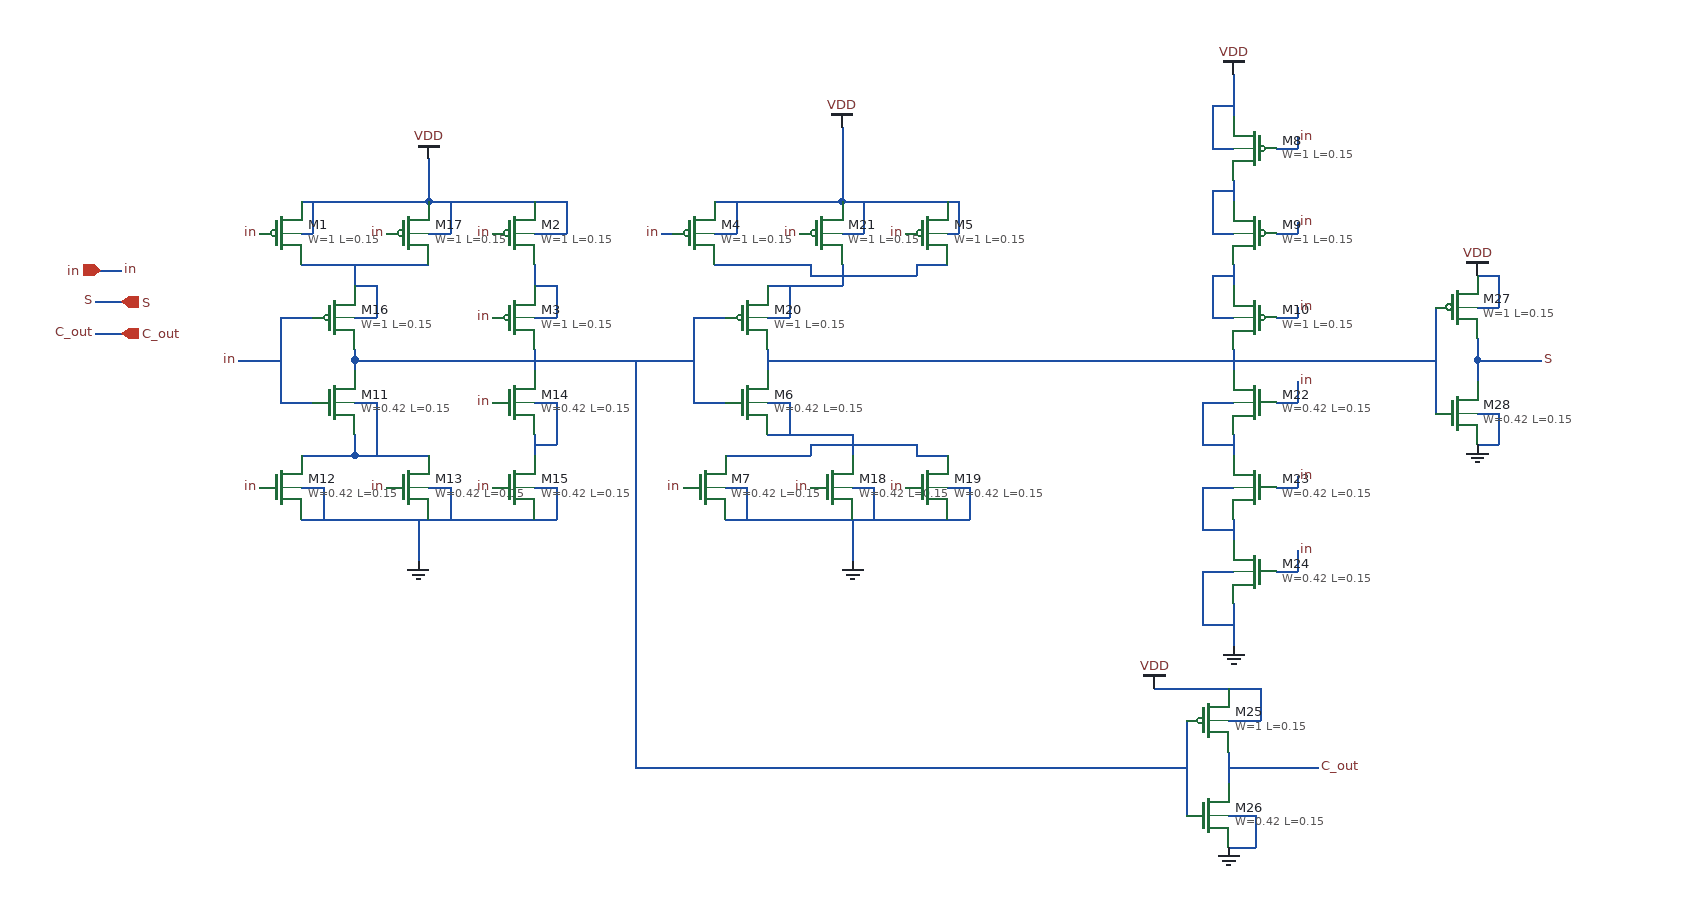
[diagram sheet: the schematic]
v {xschem version=3.4.3 file_version=1.2
}
G {}
K {}
V {}
S {}
E {}
N 60 20 180 20 {
lab=VDD}
N 180 20 280 20 {
lab=VDD}
N 180 -20 180 20 {
lab=VDD}
N 570 -50 570 20 {
lab=VDD}
N 450 20 570 20 {
lab=VDD}
N 570 20 670 20 {
lab=VDD}
N 60 80 180 80 {
lab=#net1}
N 280 80 280 100 {
lab=#net2}
N 280 160 280 180 {
lab=#net3}
N 110 170 280 170 {
lab=#net3}
N 110 160 110 170 {
lab=#net3}
N 110 170 110 180 {
lab=#net3}
N 110 80 110 100 {
lab=#net1}
N 110 240 110 260 {
lab=#net4}
N 110 260 180 260 {
lab=#net4}
N 60 260 110 260 {
lab=#net4}
N 170 320 170 360 {
lab=GND}
N 460 320 670 320 {
lab=GND}
N 580 320 580 360 {
lab=GND}
N 450 80 540 80 {
lab=#net5}
N 540 80 540 90 {
lab=#net5}
N 540 90 640 90 {
lab=#net5}
N 640 80 640 90 {
lab=#net5}
N 640 80 670 80 {
lab=#net5}
N 570 80 570 100 {
lab=#net6}
N 500 100 570 100 {
lab=#net6}
N 60 320 180 320 {
lab=GND}
N 180 320 280 320 {
lab=GND}
N 500 160 500 180 {
lab=#net7}
N 460 260 540 260 {
lab=#net8}
N 540 250 540 260 {
lab=#net8}
N 540 250 640 250 {
lab=#net8}
N 640 250 640 260 {
lab=#net8}
N 640 260 670 260 {
lab=#net8}
N 580 240 580 260 {
lab=#net9}
N 500 240 570 240 {
lab=#net9}
N 570 240 580 240 {
lab=#net9}
N 430 130 460 130 {
lab=#net3}
N 430 130 430 210 {
lab=#net3}
N 430 210 460 210 {
lab=#net3}
N 280 170 430 170 {
lab=#net3}
N 40 130 70 130 {
lab=in}
N 40 130 40 210 {
lab=in}
N 40 210 70 210 {
lab=in}
N 500 170 1070 170 {
lab=#net7}
N 940 160 940 170 {
lab=#net7}
N 940 170 940 180 {
lab=#net7}
N 940 80 940 100 {
lab=#net10}
N 940 0 940 20 {
lab=#net11}
N 940 240 940 260 {
lab=#net12}
N 940 320 940 340 {
lab=#net13}
N 940 -100 940 -60 {
lab=VDD}
N 940 400 940 440 {
lab=GND}
N -130 85 -110 85 {
lab=in}
N -135 115 -110 115 {
lab=S}
N 0 170 40 170 {
lab=in}
N 280 240 280 260 {
lab=#net14}
N 980 -30 1000 -30 {
lab=in}
N 1000 -40 1000 -30 {
lab=in}
N 1000 40 1000 50 {
lab=in}
N 980 50 1000 50 {
lab=in}
N 1000 120 1000 130 {
lab=in}
N 980 130 1000 130 {
lab=in}
N 1000 190 1000 210 {
lab=in}
N 980 210 990 210 {
lab=in}
N 990 210 1000 210 {
lab=in}
N 1000 280 1000 290 {
lab=in}
N 980 290 990 290 {
lab=in}
N 990 290 1000 290 {
lab=in}
N 1000 360 1000 370 {
lab=B}
N 980 370 1000 370 {
lab=B}
N 1000 350 1000 360 {
lab=B}
N 70 20 70 50 {
lab=VDD}
N 60 50 70 50 {
lab=VDD}
N 200 20 200 50 {
lab=VDD}
N 180 50 200 50 {
lab=VDD}
N 280 20 310 20 {
lab=VDD}
N 310 20 310 50 {
lab=VDD}
N 280 50 310 50 {
lab=VDD}
N 110 100 130 100 {
lab=#net1}
N 130 100 130 130 {
lab=#net1}
N 110 130 120 130 {
lab=#net1}
N 120 130 130 130 {
lab=#net1}
N 280 100 300 100 {
lab=#net2}
N 300 100 300 130 {
lab=#net2}
N 280 130 300 130 {
lab=#net2}
N 470 20 470 50 {
lab=VDD}
N 450 50 470 50 {
lab=VDD}
N 110 210 130 210 {
lab=#net4}
N 130 210 130 260 {
lab=#net4}
N 60 290 80 290 {
lab=GND}
N 80 290 80 320 {
lab=GND}
N 180 290 200 290 {
lab=GND}
N 200 290 200 320 {
lab=GND}
N 280 290 300 290 {
lab=GND}
N 300 290 300 320 {
lab=GND}
N 280 320 300 320 {
lab=GND}
N 460 290 480 290 {
lab=GND}
N 480 290 480 320 {
lab=GND}
N 500 210 520 210 {
lab=#net9}
N 520 210 520 240 {
lab=#net9}
N 500 130 520 130 {
lab=#net6}
N 520 100 520 130 {
lab=#net6}
N 580 290 600 290 {
lab=GND}
N 600 290 600 320 {
lab=GND}
N 670 290 690 290 {
lab=GND}
N 690 290 690 320 {
lab=GND}
N 670 320 690 320 {
lab=GND}
N 570 50 590 50 {
lab=VDD}
N 590 20 590 50 {
lab=VDD}
N 670 50 680 50 {
lab=VDD}
N 680 20 680 50 {
lab=VDD}
N 670 20 680 20 {
lab=VDD}
N 920 50 940 50 {
lab=#net11}
N 920 10 920 50 {
lab=#net11}
N 920 10 940 10 {
lab=#net11}
N 920 130 940 130 {
lab=#net10}
N 920 90 920 130 {
lab=#net10}
N 920 90 940 90 {
lab=#net10}
N 910 210 940 210 {
lab=#net12}
N 910 210 910 250 {
lab=#net12}
N 910 250 940 250 {
lab=#net12}
N 910 290 940 290 {
lab=#net13}
N 910 290 910 330 {
lab=#net13}
N 910 330 940 330 {
lab=#net13}
N 910 370 940 370 {
lab=GND}
N 910 370 910 420 {
lab=GND}
N 910 420 940 420 {
lab=GND}
N 280 210 300 210 {
lab=#net14}
N 300 210 300 250 {
lab=#net14}
N 280 250 300 250 {
lab=#net14}
N 920 -30 940 -30 {
lab=VDD}
N 920 -70 920 -30 {
lab=VDD}
N 920 -70 940 -70 {
lab=VDD}
N 1070 170 1130 170 {
lab=#net7}
N 1130 140 1130 220 {
lab=#net7}
N 1170 170 1170 190 {
lab=S}
N 1130 130 1130 140 {
lab=#net7}
N 1170 160 1170 170 {
lab=S}
N 1170 170 1230 170 {
lab=S}
N 1170 150 1170 160 {
lab=S}
N 1130 120 1130 130 {
lab=#net7}
N 1170 120 1190 120 {
lab=VDD}
N 1190 90 1190 120 {
lab=VDD}
N 1170 90 1190 90 {
lab=VDD}
N 1170 220 1190 220 {
lab=GND}
N 1170 250 1190 250 {
lab=GND}
N 1190 220 1190 250 {
lab=GND}
N 375 170 375 555 {
lab=#net3}
N 375 555 870 555 {
lab=#net3}
N 870 555 895 555 {
lab=#net3}
N 935 550 935 570 {
lab=C_out}
N 935 540 935 550 {
lab=C_out}
N 935 555 1020 555 {
lab=C_out}
N 865 480 935 480 {
lab=VDD}
N 935 510 965 510 {
lab=VDD}
N 965 480 965 510 {
lab=VDD}
N 935 480 965 480 {
lab=VDD}
N 935 600 960 600 {
lab=GND}
N 960 600 960 630 {
lab=GND}
N 945 630 960 630 {
lab=GND}
N 935 630 945 630 {
lab=GND}
N -135 145 -110 145 {
lab=C_out}
N 895 510 895 600 {
lab=#net3}
N 400 50 410 50 {
lab=in}
C {sky130_fd_pr/pfet_01v8.sym} 40 50 0 0 {name=M1
L=0.15
W=1
nf=1
mult=1
ad="'int((nf+1)/2) * W/nf * 0.29'" 
pd="'2*int((nf+1)/2) * (W/nf + 0.29)'"
as="'int((nf+2)/2) * W/nf * 0.29'" 
ps="'2*int((nf+2)/2) * (W/nf + 0.29)'"
nrd="'0.29 / W'" nrs="'0.29 / W'"
sa=0 sb=0 sd=0
model=pfet_01v8
spiceprefix=X
}
C {sky130_fd_pr/pfet_01v8.sym} 260 50 0 0 {name=M2
L=0.15
W=1
nf=1
mult=1
ad="'int((nf+1)/2) * W/nf * 0.29'" 
pd="'2*int((nf+1)/2) * (W/nf + 0.29)'"
as="'int((nf+2)/2) * W/nf * 0.29'" 
ps="'2*int((nf+2)/2) * (W/nf + 0.29)'"
nrd="'0.29 / W'" nrs="'0.29 / W'"
sa=0 sb=0 sd=0
model=pfet_01v8
spiceprefix=X
}
C {sky130_fd_pr/pfet_01v8.sym} 260 130 0 0 {name=M3
L=0.15
W=1
nf=1
mult=1
ad="'int((nf+1)/2) * W/nf * 0.29'" 
pd="'2*int((nf+1)/2) * (W/nf + 0.29)'"
as="'int((nf+2)/2) * W/nf * 0.29'" 
ps="'2*int((nf+2)/2) * (W/nf + 0.29)'"
nrd="'0.29 / W'" nrs="'0.29 / W'"
sa=0 sb=0 sd=0
model=pfet_01v8
spiceprefix=X
}
C {sky130_fd_pr/pfet_01v8.sym} 960 -30 0 1 {name=M8
L=0.15
W=1
nf=1
mult=1
ad="'int((nf+1)/2) * W/nf * 0.29'" 
pd="'2*int((nf+1)/2) * (W/nf + 0.29)'"
as="'int((nf+2)/2) * W/nf * 0.29'" 
ps="'2*int((nf+2)/2) * (W/nf + 0.29)'"
nrd="'0.29 / W'" nrs="'0.29 / W'"
sa=0 sb=0 sd=0
model=pfet_01v8
spiceprefix=X
}
C {sky130_fd_pr/pfet_01v8.sym} 960 50 0 1 {name=M9
L=0.15
W=1
nf=1
mult=1
ad="'int((nf+1)/2) * W/nf * 0.29'" 
pd="'2*int((nf+1)/2) * (W/nf + 0.29)'"
as="'int((nf+2)/2) * W/nf * 0.29'" 
ps="'2*int((nf+2)/2) * (W/nf + 0.29)'"
nrd="'0.29 / W'" nrs="'0.29 / W'"
sa=0 sb=0 sd=0
model=pfet_01v8
spiceprefix=X
}
C {sky130_fd_pr/pfet_01v8.sym} 960 130 0 1 {name=M10
L=0.15
W=1
nf=1
mult=1
ad="'int((nf+1)/2) * W/nf * 0.29'" 
pd="'2*int((nf+1)/2) * (W/nf + 0.29)'"
as="'int((nf+2)/2) * W/nf * 0.29'" 
ps="'2*int((nf+2)/2) * (W/nf + 0.29)'"
nrd="'0.29 / W'" nrs="'0.29 / W'"
sa=0 sb=0 sd=0
model=pfet_01v8
spiceprefix=X
}
C {sky130_fd_pr/nfet_01v8.sym} 90 210 0 0 {name=M11
L=0.15
W=0.42
nf=1 
mult=1
ad="'int((nf+1)/2) * W/nf * 0.29'" 
pd="'2*int((nf+1)/2) * (W/nf + 0.29)'"
as="'int((nf+2)/2) * W/nf * 0.29'" 
ps="'2*int((nf+2)/2) * (W/nf + 0.29)'"
nrd="'0.29 / W'" nrs="'0.29 / W'"
sa=0 sb=0 sd=0
model=nfet_01v8
spiceprefix=X
}
C {sky130_fd_pr/nfet_01v8.sym} 40 290 0 0 {name=M12
L=0.15
W=0.42
nf=1 
mult=1
ad="'int((nf+1)/2) * W/nf * 0.29'" 
pd="'2*int((nf+1)/2) * (W/nf + 0.29)'"
as="'int((nf+2)/2) * W/nf * 0.29'" 
ps="'2*int((nf+2)/2) * (W/nf + 0.29)'"
nrd="'0.29 / W'" nrs="'0.29 / W'"
sa=0 sb=0 sd=0
model=nfet_01v8
spiceprefix=X
}
C {sky130_fd_pr/nfet_01v8.sym} 160 290 0 0 {name=M13
L=0.15
W=0.42
nf=1 
mult=1
ad="'int((nf+1)/2) * W/nf * 0.29'" 
pd="'2*int((nf+1)/2) * (W/nf + 0.29)'"
as="'int((nf+2)/2) * W/nf * 0.29'" 
ps="'2*int((nf+2)/2) * (W/nf + 0.29)'"
nrd="'0.29 / W'" nrs="'0.29 / W'"
sa=0 sb=0 sd=0
model=nfet_01v8
spiceprefix=X
}
C {sky130_fd_pr/nfet_01v8.sym} 260 210 0 0 {name=M14
L=0.15
W=0.42
nf=1 
mult=1
ad="'int((nf+1)/2) * W/nf * 0.29'" 
pd="'2*int((nf+1)/2) * (W/nf + 0.29)'"
as="'int((nf+2)/2) * W/nf * 0.29'" 
ps="'2*int((nf+2)/2) * (W/nf + 0.29)'"
nrd="'0.29 / W'" nrs="'0.29 / W'"
sa=0 sb=0 sd=0
model=nfet_01v8
spiceprefix=X
}
C {sky130_fd_pr/nfet_01v8.sym} 260 290 0 0 {name=M15
L=0.15
W=0.42
nf=1 
mult=1
ad="'int((nf+1)/2) * W/nf * 0.29'" 
pd="'2*int((nf+1)/2) * (W/nf + 0.29)'"
as="'int((nf+2)/2) * W/nf * 0.29'" 
ps="'2*int((nf+2)/2) * (W/nf + 0.29)'"
nrd="'0.29 / W'" nrs="'0.29 / W'"
sa=0 sb=0 sd=0
model=nfet_01v8
spiceprefix=X
}
C {sky130_fd_pr/pfet_01v8.sym} 90 130 0 0 {name=M16
L=0.15
W=1
nf=1
mult=1
ad="'int((nf+1)/2) * W/nf * 0.29'" 
pd="'2*int((nf+1)/2) * (W/nf + 0.29)'"
as="'int((nf+2)/2) * W/nf * 0.29'" 
ps="'2*int((nf+2)/2) * (W/nf + 0.29)'"
nrd="'0.29 / W'" nrs="'0.29 / W'"
sa=0 sb=0 sd=0
model=pfet_01v8
spiceprefix=X
}
C {sky130_fd_pr/pfet_01v8.sym} 160 50 0 0 {name=M17
L=0.15
W=1
nf=1
mult=1
ad="'int((nf+1)/2) * W/nf * 0.29'" 
pd="'2*int((nf+1)/2) * (W/nf + 0.29)'"
as="'int((nf+2)/2) * W/nf * 0.29'" 
ps="'2*int((nf+2)/2) * (W/nf + 0.29)'"
nrd="'0.29 / W'" nrs="'0.29 / W'"
sa=0 sb=0 sd=0
model=pfet_01v8
spiceprefix=X
}
C {sky130_fd_pr/pfet_01v8.sym} 430 50 0 0 {name=M4
L=0.15
W=1
nf=1
mult=1
ad="'int((nf+1)/2) * W/nf * 0.29'" 
pd="'2*int((nf+1)/2) * (W/nf + 0.29)'"
as="'int((nf+2)/2) * W/nf * 0.29'" 
ps="'2*int((nf+2)/2) * (W/nf + 0.29)'"
nrd="'0.29 / W'" nrs="'0.29 / W'"
sa=0 sb=0 sd=0
model=pfet_01v8
spiceprefix=X
}
C {sky130_fd_pr/pfet_01v8.sym} 650 50 0 0 {name=M5
L=0.15
W=1
nf=1
mult=1
ad="'int((nf+1)/2) * W/nf * 0.29'" 
pd="'2*int((nf+1)/2) * (W/nf + 0.29)'"
as="'int((nf+2)/2) * W/nf * 0.29'" 
ps="'2*int((nf+2)/2) * (W/nf + 0.29)'"
nrd="'0.29 / W'" nrs="'0.29 / W'"
sa=0 sb=0 sd=0
model=pfet_01v8
spiceprefix=X
}
C {sky130_fd_pr/nfet_01v8.sym} 480 210 0 0 {name=M6
L=0.15
W=0.42
nf=1 
mult=1
ad="'int((nf+1)/2) * W/nf * 0.29'" 
pd="'2*int((nf+1)/2) * (W/nf + 0.29)'"
as="'int((nf+2)/2) * W/nf * 0.29'" 
ps="'2*int((nf+2)/2) * (W/nf + 0.29)'"
nrd="'0.29 / W'" nrs="'0.29 / W'"
sa=0 sb=0 sd=0
model=nfet_01v8
spiceprefix=X
}
C {sky130_fd_pr/nfet_01v8.sym} 440 290 0 0 {name=M7
L=0.15
W=0.42
nf=1 
mult=1
ad="'int((nf+1)/2) * W/nf * 0.29'" 
pd="'2*int((nf+1)/2) * (W/nf + 0.29)'"
as="'int((nf+2)/2) * W/nf * 0.29'" 
ps="'2*int((nf+2)/2) * (W/nf + 0.29)'"
nrd="'0.29 / W'" nrs="'0.29 / W'"
sa=0 sb=0 sd=0
model=nfet_01v8
spiceprefix=X
}
C {sky130_fd_pr/nfet_01v8.sym} 560 290 0 0 {name=M18
L=0.15
W=0.42
nf=1 
mult=1
ad="'int((nf+1)/2) * W/nf * 0.29'" 
pd="'2*int((nf+1)/2) * (W/nf + 0.29)'"
as="'int((nf+2)/2) * W/nf * 0.29'" 
ps="'2*int((nf+2)/2) * (W/nf + 0.29)'"
nrd="'0.29 / W'" nrs="'0.29 / W'"
sa=0 sb=0 sd=0
model=nfet_01v8
spiceprefix=X
}
C {sky130_fd_pr/nfet_01v8.sym} 650 290 0 0 {name=M19
L=0.15
W=0.42
nf=1 
mult=1
ad="'int((nf+1)/2) * W/nf * 0.29'" 
pd="'2*int((nf+1)/2) * (W/nf + 0.29)'"
as="'int((nf+2)/2) * W/nf * 0.29'" 
ps="'2*int((nf+2)/2) * (W/nf + 0.29)'"
nrd="'0.29 / W'" nrs="'0.29 / W'"
sa=0 sb=0 sd=0
model=nfet_01v8
spiceprefix=X
}
C {sky130_fd_pr/pfet_01v8.sym} 480 130 0 0 {name=M20
L=0.15
W=1
nf=1
mult=1
ad="'int((nf+1)/2) * W/nf * 0.29'" 
pd="'2*int((nf+1)/2) * (W/nf + 0.29)'"
as="'int((nf+2)/2) * W/nf * 0.29'" 
ps="'2*int((nf+2)/2) * (W/nf + 0.29)'"
nrd="'0.29 / W'" nrs="'0.29 / W'"
sa=0 sb=0 sd=0
model=pfet_01v8
spiceprefix=X
}
C {sky130_fd_pr/pfet_01v8.sym} 550 50 0 0 {name=M21
L=0.15
W=1
nf=1
mult=1
ad="'int((nf+1)/2) * W/nf * 0.29'" 
pd="'2*int((nf+1)/2) * (W/nf + 0.29)'"
as="'int((nf+2)/2) * W/nf * 0.29'" 
ps="'2*int((nf+2)/2) * (W/nf + 0.29)'"
nrd="'0.29 / W'" nrs="'0.29 / W'"
sa=0 sb=0 sd=0
model=pfet_01v8
spiceprefix=X
}
C {sky130_fd_pr/nfet_01v8.sym} 960 210 0 1 {name=M22
L=0.15
W=0.42
nf=1 
mult=1
ad="'int((nf+1)/2) * W/nf * 0.29'" 
pd="'2*int((nf+1)/2) * (W/nf + 0.29)'"
as="'int((nf+2)/2) * W/nf * 0.29'" 
ps="'2*int((nf+2)/2) * (W/nf + 0.29)'"
nrd="'0.29 / W'" nrs="'0.29 / W'"
sa=0 sb=0 sd=0
model=nfet_01v8
spiceprefix=X
}
C {sky130_fd_pr/nfet_01v8.sym} 960 290 0 1 {name=M23
L=0.15
W=0.42
nf=1 
mult=1
ad="'int((nf+1)/2) * W/nf * 0.29'" 
pd="'2*int((nf+1)/2) * (W/nf + 0.29)'"
as="'int((nf+2)/2) * W/nf * 0.29'" 
ps="'2*int((nf+2)/2) * (W/nf + 0.29)'"
nrd="'0.29 / W'" nrs="'0.29 / W'"
sa=0 sb=0 sd=0
model=nfet_01v8
spiceprefix=X
}
C {sky130_fd_pr/nfet_01v8.sym} 960 370 0 1 {name=M24
L=0.15
W=0.42
nf=1 
mult=1
ad="'int((nf+1)/2) * W/nf * 0.29'" 
pd="'2*int((nf+1)/2) * (W/nf + 0.29)'"
as="'int((nf+2)/2) * W/nf * 0.29'" 
ps="'2*int((nf+2)/2) * (W/nf + 0.29)'"
nrd="'0.29 / W'" nrs="'0.29 / W'"
sa=0 sb=0 sd=0
model=nfet_01v8
spiceprefix=X
}
C {devices/ipin.sym} -130 85 0 0 {name=p17 lab=in}
C {devices/lab_pin.sym} -110 85 0 1 {name=p18 sig_type=std_logic lab=in}
C {devices/opin.sym} -110 115 0 0 {name=p29 lab=S}
C {devices/lab_pin.sym} -135 115 0 0 {name=p31 sig_type=std_logic lab=S}
C {devices/lab_pin.sym} 1000 190 0 1 {name=p48 sig_type=std_logic lab=in}
C {devices/lab_pin.sym} 1000 120 0 1 {name=p44 sig_type=std_logic lab=in}
C {devices/lab_pin.sym} 1000 280 0 1 {name=p32 sig_type=std_logic lab=in}
C {devices/lab_pin.sym} 1000 350 0 1 {name=p40 sig_type=std_logic lab=in}
C {devices/lab_pin.sym} 1000 40 0 1 {name=p30 sig_type=std_logic lab=in}
C {devices/lab_pin.sym} 1000 -40 0 1 {name=p39 sig_type=std_logic lab=in}
C {devices/lab_pin.sym} 630 50 0 0 {name=p42 sig_type=std_logic lab=in}
C {devices/lab_pin.sym} 400 50 0 0 {name=p24 sig_type=std_logic lab=in}
C {devices/lab_pin.sym} 530 50 0 0 {name=p38 sig_type=std_logic lab=in}
C {devices/lab_pin.sym} 420 290 0 0 {name=p23 sig_type=std_logic lab=in}
C {devices/lab_pin.sym} 540 290 0 0 {name=p37 sig_type=std_logic lab=in}
C {devices/lab_pin.sym} 630 290 0 0 {name=p43 sig_type=std_logic lab=in}
C {devices/lab_pin.sym} 20 50 0 0 {name=p19 sig_type=std_logic lab=in}
C {devices/lab_pin.sym} 20 290 0 0 {name=p20 sig_type=std_logic lab=in}
C {devices/lab_pin.sym} 0 170 0 0 {name=p21 sig_type=std_logic lab=in}
C {devices/lab_pin.sym} 140 50 0 0 {name=p22 sig_type=std_logic lab=in}
C {devices/lab_pin.sym} 140 290 0 0 {name=p33 sig_type=std_logic lab=in}
C {devices/lab_pin.sym} 240 290 0 0 {name=p34 sig_type=std_logic lab=in}
C {devices/lab_pin.sym} 240 50 0 0 {name=p35 sig_type=std_logic lab=in}
C {devices/lab_pin.sym} 240 130 0 0 {name=p36 sig_type=std_logic lab=in}
C {devices/lab_pin.sym} 240 210 0 0 {name=p41 sig_type=std_logic lab=in}
C {devices/vdd.sym} 180 -20 0 0 {name=l1 lab=VDD}
C {devices/vdd.sym} 570 -50 0 0 {name=l2 lab=VDD}
C {devices/vdd.sym} 940 -100 0 0 {name=l3 lab=VDD}
C {devices/gnd.sym} 170 360 0 0 {name=l4 lab=GND}
C {devices/gnd.sym} 580 360 0 0 {name=l5 lab=GND}
C {devices/gnd.sym} 940 440 0 0 {name=l6 lab=GND}
C {sky130_fd_pr/pfet_01v8.sym} 915 510 0 0 {name=M25
L=0.15
W=1
nf=1
mult=1
ad="'int((nf+1)/2) * W/nf * 0.29'" 
pd="'2*int((nf+1)/2) * (W/nf + 0.29)'"
as="'int((nf+2)/2) * W/nf * 0.29'" 
ps="'2*int((nf+2)/2) * (W/nf + 0.29)'"
nrd="'0.29 / W'" nrs="'0.29 / W'"
sa=0 sb=0 sd=0
model=pfet_01v8
spiceprefix=X
}
C {sky130_fd_pr/nfet_01v8.sym} 915 600 0 0 {name=M26
L=0.15
W=0.42
nf=1 
mult=1
ad="'int((nf+1)/2) * W/nf * 0.29'" 
pd="'2*int((nf+1)/2) * (W/nf + 0.29)'"
as="'int((nf+2)/2) * W/nf * 0.29'" 
ps="'2*int((nf+2)/2) * (W/nf + 0.29)'"
nrd="'0.29 / W'" nrs="'0.29 / W'"
sa=0 sb=0 sd=0
model=nfet_01v8
spiceprefix=X
}
C {sky130_fd_pr/pfet_01v8.sym} 1150 120 0 0 {name=M27
L=0.15
W=1
nf=1
mult=1
ad="'int((nf+1)/2) * W/nf * 0.29'" 
pd="'2*int((nf+1)/2) * (W/nf + 0.29)'"
as="'int((nf+2)/2) * W/nf * 0.29'" 
ps="'2*int((nf+2)/2) * (W/nf + 0.29)'"
nrd="'0.29 / W'" nrs="'0.29 / W'"
sa=0 sb=0 sd=0
model=pfet_01v8
spiceprefix=X
}
C {sky130_fd_pr/nfet_01v8.sym} 1150 220 0 0 {name=M28
L=0.15
W=0.42
nf=1 
mult=1
ad="'int((nf+1)/2) * W/nf * 0.29'" 
pd="'2*int((nf+1)/2) * (W/nf + 0.29)'"
as="'int((nf+2)/2) * W/nf * 0.29'" 
ps="'2*int((nf+2)/2) * (W/nf + 0.29)'"
nrd="'0.29 / W'" nrs="'0.29 / W'"
sa=0 sb=0 sd=0
model=nfet_01v8
spiceprefix=X
}
C {devices/lab_pin.sym} 1230 170 0 1 {name=p47 sig_type=std_logic lab=S}
C {devices/vdd.sym} 1170 90 0 0 {name=l7 lab=VDD}
C {devices/gnd.sym} 1170 250 0 0 {name=l8 lab=GND}
C {devices/vdd.sym} 865 480 0 0 {name=l9 lab=VDD}
C {devices/gnd.sym} 935 630 0 0 {name=l10 lab=GND}
C {devices/opin.sym} -110 145 0 0 {name=p1 lab=C_out}
C {devices/lab_pin.sym} -135 145 0 0 {name=p2 sig_type=std_logic lab=C_out}
C {devices/lab_pin.sym} 1020 555 0 1 {name=p3 sig_type=std_logic lab=C_out}
